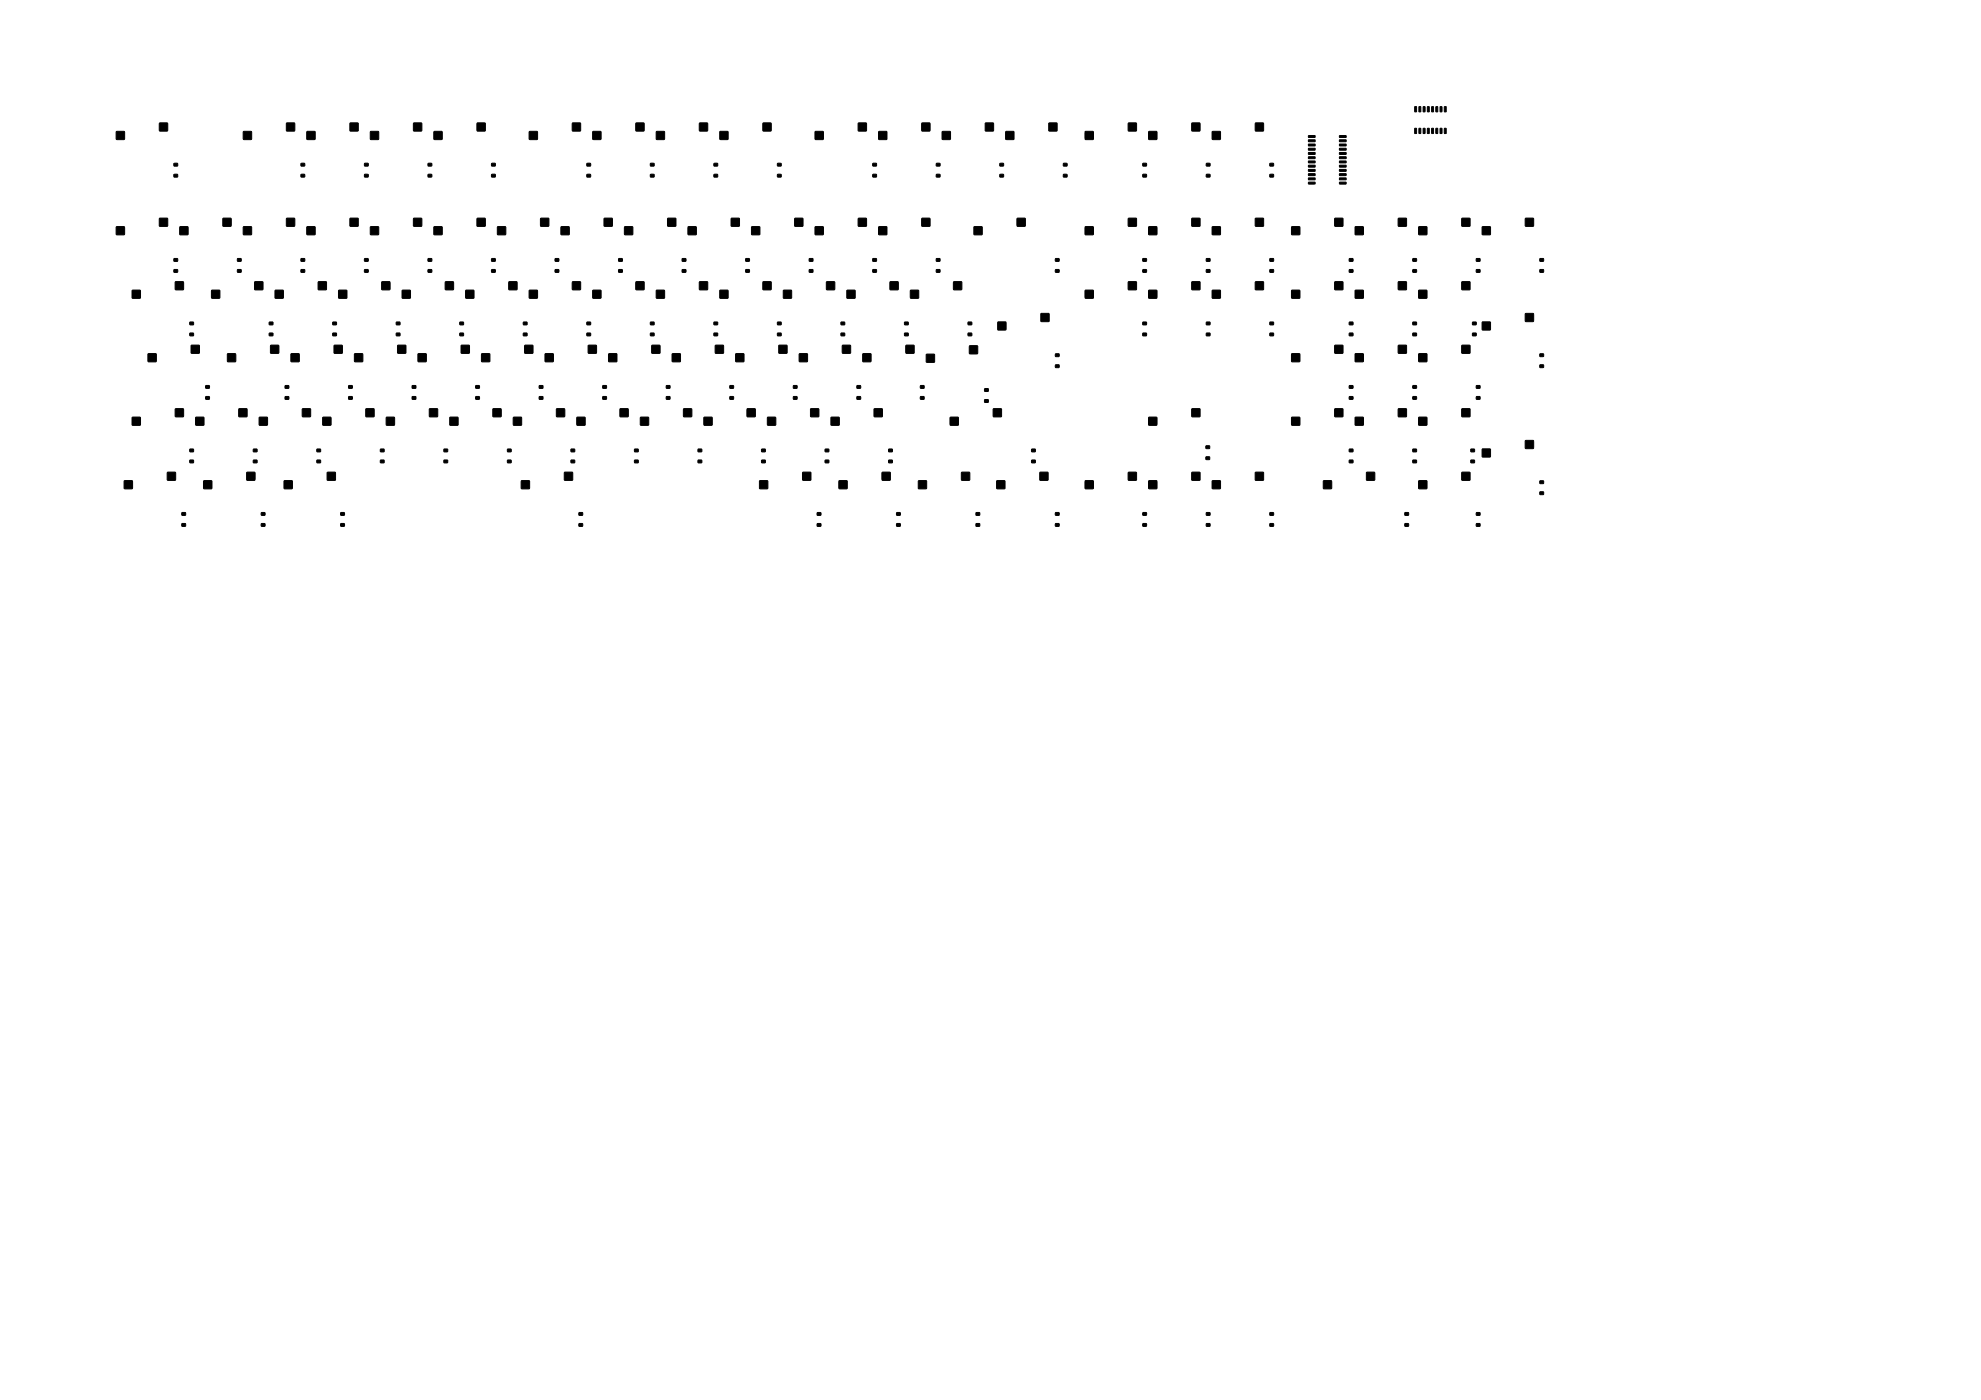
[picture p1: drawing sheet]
<svg xmlns="http://www.w3.org/2000/svg" width="594mm" height="420mm" viewBox="0 0 594 420" stroke-linecap="round" stroke-linejoin="round" font-family="sans-serif">
<g fill="#000" stroke="#000" stroke-width=".3">
<path d="M34.9 39.5h2.4v2.3h-2.4zM47.8 36.9h2.4v2.4h-2.4zM73 39.5h2.4v2.3h-2.4zM85.9 36.9h2.4v2.4h-2.4zM92 39.5h2.4v2.3h-2.4zM105 36.9h2.4v2.4h-2.4zM111.1 39.5h2.4v2.3h-2.4zM124 36.9h2.4v2.4h-2.4zM130.1 39.5h2.4v2.3h-2.4zM143.1 36.9h2.4v2.4h-2.4zM158.7 39.5h2.4v2.3h-2.4zM171.6 36.9h2.4v2.4h-2.4z"/>
<path d="M177.8 39.5h2.4v2.3h-2.4zM190.7 36.9h2.4v2.4h-2.4zM196.8 39.5h2.4v2.3h-2.4zM209.7 36.9h2.4v2.4h-2.4zM215.9 39.5h2.4v2.3h-2.4zM228.8 36.9h2.4v2.4h-2.4zM244.4 39.5h2.4v2.3h-2.4zM257.4 36.9h2.4v2.4h-2.4zM263.5 39.5h2.4v2.3h-2.4zM276.4 36.9h2.4v2.4h-2.4zM282.5 39.5h2.4v2.3h-2.4zM295.5 36.9h2.4v2.4h-2.4z"/>
<path d="M301.6 39.5h2.4v2.3h-2.4zM314.5 36.9h2.4v2.4h-2.4zM325.4 39.5h2.4v2.3h-2.4zM338.3 36.9h2.4v2.4h-2.4zM344.5 39.5h2.4v2.3h-2.4zM357.4 36.9h2.4v2.4h-2.4zM363.5 39.5h2.4v2.3h-2.4zM376.4 36.9h2.4v2.4h-2.4zM424.2 32l.6 .1-.1 1.5-.5-.1zM424.2 38.5l.6 .1-.1 1.5-.5-.1zM425.5 32l.5 .1v1.5l-.5-.1zM425.5 38.5l.5 .1v1.5l-.5-.1z"/>
<path d="M426.8 32l.5 .1-.1 1.5-.5-.1zM426.8 38.5l.5 .1-.1 1.5-.5-.1zM428 32l.6 .1-.1 1.5-.5-.1zM428 38.5l.6 .1-.1 1.5-.5-.1zM429.3 32l.5 .1v1.5l-.5-.1zM429.3 38.5l.5 .1v1.5l-.5-.1zM430.6 32l.5 .1-.1 1.5-.5-.1zM430.6 38.5l.5 .1-.1 1.5-.5-.1zM431.8 32l.6 .1-.1 1.5-.5-.1zM431.8 38.5l.6 .1-.1 1.5-.5-.1zM433.1 32l.6 .1-.1 1.5-.5-.1zM433.1 38.5l.6 .1-.1 1.5-.5-.1z"/>
<path d="M52.2 52.3h1v.8h-1zM52.2 49h1v.8h-1zM90.3 52.3h1v.8h-1zM90.3 49h1v.8h-1zM109.3 52.3h1.1v.8h-1.1zM109.3 49h1.1v.8h-1.1zM128.4 52.3h1v.8h-1zM128.4 49h1v.8h-1zM147.4 52.3h1.1v.8h-1.1zM147.4 49h1.1v.8h-1.1zM176 52.3h1.1v.8h-1.1zM176 49h1.1v.8h-1.1z"/>
<path d="M195 52.3h1.1v.8h-1.1zM195 49h1.1v.8h-1.1zM214.1 52.3h1.1v.8h-1.1zM214.1 49h1.1v.8h-1.1zM233.1 52.3h1.1v.8h-1.1zM233.1 49h1.1v.8h-1.1zM261.7 52.3h1.1v.8h-1.1zM261.7 49h1.1v.8h-1.1zM280.8 52.3h1v.8h-1zM280.8 49h1v.8h-1zM299.8 52.3h1.1v.8h-1.1zM299.8 49h1.1v.8h-1.1z"/>
<path d="M318.9 52.3h1v.8h-1zM318.9 49h1v.8h-1zM342.7 52.3h1.1v.8h-1.1zM342.7 49h1.1v.8h-1.1zM361.7 52.3h1.1v.8h-1.1zM361.7 49h1.1v.8h-1.1zM380.8 52.3h1.1v.8h-1.1zM380.8 49h1.1v.8h-1.1zM392.4 54.7l1.9-.1 .1 .5-2 .1zM392.4 53.4h1.9l.1 .5h-2zM392.4 52.1h1.9l.1 .5-2 .1zM392.4 50.9l1.9-.1 .1 .5-2 .1z"/>
<path d="M392.4 49.6h1.9l.1 .5h-2zM392.4 48.3h1.9l.1 .5-2 .1zM392.4 47.1l1.9-.1 .1 .5-2 .1zM392.4 45.8l1.9-.1 .1 .5-2 .1zM392.4 44.5h1.9l.1 .5-2 .1zM392.4 43.2h1.9l.1 .5-2 .1zM392.4 42l1.9-.1 .1 .5-2 .1zM392.4 40.7h1.9l.1 .5h-2zM401.7 40.7h1.9v.5h-1.9zM401.7 42l1.9-.1v.5l-1.9 .1zM401.7 43.2h1.9v.5l-1.9 .1zM401.7 44.5h1.9v.5l-1.9 .1z"/>
<path d="M401.7 45.8l1.9-.1v.5l-1.9 .1zM401.7 47.1l1.9-.1v.5l-1.9 .1zM401.7 48.3h1.9v.5l-1.9 .1zM401.7 49.6h1.9v.5h-1.9zM401.7 50.9l1.9-.1v.5l-1.9 .1zM401.7 52.1h1.9v.5l-1.9 .1zM401.7 53.4h1.9v.5h-1.9zM401.7 54.7l1.9-.1v.5l-1.9 .1zM34.9 68h2.4v2.4h-2.4zM47.8 65.5h2.4v2.4h-2.4zM52.2 77.6h1v.8h-1zM53.9 68h2.4v2.4h-2.4z"/>
<path d="M66.9 65.5h2.4v2.4h-2.4zM71.2 77.6h1.1v.8h-1.1zM73 68h2.4v2.4h-2.4zM85.9 65.5h2.4v2.4h-2.4zM90.3 77.6h1v.8h-1zM92 68h2.4v2.4h-2.4zM105 65.5h2.4v2.4h-2.4zM109.3 77.6h1.1v.8h-1.1zM111.1 68h2.4v2.4h-2.4zM124 65.5h2.4v2.4h-2.4zM128.4 77.6h1v.8h-1zM130.1 68h2.4v2.4h-2.4z"/>
<path d="M143.1 65.5h2.4v2.4h-2.4zM147.4 77.6h1.1v.8h-1.1zM149.2 68h2.4v2.4h-2.4zM162.1 65.5h2.4v2.4h-2.4zM166.5 77.6h1v.8h-1zM168.2 68h2.4v2.4h-2.4zM181.2 65.5h2.4v2.4h-2.4zM185.5 77.6h1.1v.8h-1.1zM187.3 68h2.4v2.4h-2.4zM200.2 65.5h2.4v2.4h-2.4zM204.6 77.6h1v.8h-1zM206.3 68h2.4v2.4h-2.4z"/>
<path d="M219.3 65.5h2.4v2.4h-2.4zM223.6 77.6h1.1v.8h-1.1zM225.4 68h2.4v2.4h-2.4zM238.3 65.5h2.4v2.4h-2.4zM242.7 77.6h1v.8h-1zM244.4 68h2.4v2.4h-2.4zM257.4 65.5h2.4v2.4h-2.4zM261.7 77.6h1.1v.8h-1.1zM263.5 68h2.4v2.4h-2.4zM276.4 65.5h2.4v2.4h-2.4zM280.8 77.6h1v.8h-1zM292.1 68h2.4v2.4h-2.4z"/>
<path d="M305 65.5h2.4v2.4h-2.4zM316.5 77.6h1.1v.8h-1.1zM325.4 68h2.4v2.4h-2.4zM338.3 65.5h2.4v2.4h-2.4zM342.7 77.6h1.1v.8h-1.1zM344.5 68h2.4v2.4h-2.4zM357.4 65.5h2.4v2.4h-2.4zM361.7 77.6h1.1v.8h-1.1zM363.5 68h2.4v2.4h-2.4zM376.4 65.5h2.4v2.4h-2.4zM380.8 77.6h1.1v.8h-1.1zM387.3 68h2.4v2.4h-2.4z"/>
<path d="M400.2 65.5h2.4v2.4h-2.4zM404.6 77.6h1.1v.8h-1.1zM406.4 68h2.4v2.4h-2.4zM419.3 65.5h2.4v2.4h-2.4zM423.6 77.6h1.1v.8h-1.1zM425.4 68h2.4v2.4h-2.4zM438.3 65.5h2.4v2.4h-2.4zM442.7 77.6h1.1v.8h-1.1zM444.5 68h2.4v2.4h-2.4zM457.4 65.5h2.4v2.4h-2.4zM461.7 77.6h1.1v.8h-1.1zM39.7 87.1h2.4v2.3h-2.4z"/>
<path d="M52.2 80.9h1v.8h-1zM52.6 84.5h2.4v2.4h-2.4zM56.9 96.6h1.1v.8h-1.1zM63.5 87.1h2.4v2.3h-2.4zM71.2 80.9h1.1v.8h-1.1zM76.4 84.5h2.4v2.4h-2.4zM80.7 96.6h1.1v.8h-1.1zM82.5 87.1h2.4v2.3h-2.4zM90.3 80.9h1v.8h-1zM95.4 84.5h2.4v2.4h-2.4zM99.8 96.6h1.1v.8h-1.1zM101.6 87.1h2.4v2.3h-2.4z"/>
<path d="M109.3 80.9h1.1v.8h-1.1zM114.5 84.5h2.4v2.4h-2.4zM118.8 96.6h1.1v.8h-1.1zM120.6 87.1h2.4v2.3h-2.4zM128.4 80.9h1v.8h-1zM133.5 84.5h2.4v2.4h-2.4zM137.9 96.6h1.1v.8h-1.1zM139.7 87.1h2.4v2.3h-2.4zM147.4 80.9h1.1v.8h-1.1zM152.6 84.5h2.4v2.4h-2.4zM156.9 96.6h1.1v.8h-1.1zM158.7 87.1h2.4v2.3h-2.4z"/>
<path d="M166.5 80.9h1v.8h-1zM171.6 84.5h2.4v2.4h-2.4zM176 96.6h1.1v.8h-1.1zM177.8 87.1h2.4v2.3h-2.4zM185.5 80.9h1.1v.8h-1.1zM190.7 84.5h2.4v2.4h-2.4zM195 96.6h1.1v.8h-1.1zM196.8 87.1h2.4v2.3h-2.4zM204.6 80.9h1v.8h-1zM209.7 84.5h2.4v2.4h-2.4zM214.1 96.6h1.1v.8h-1.1zM215.9 87.1h2.4v2.3h-2.4z"/>
<path d="M223.6 80.9h1.1v.8h-1.1zM228.8 84.5h2.4v2.4h-2.4zM233.1 96.6h1.1v.8h-1.1zM234.9 87.1h2.4v2.3h-2.4zM242.7 80.9h1v.8h-1zM247.8 84.5h2.4v2.4h-2.4zM252.2 96.6h1.1v.8h-1.1zM254 87.1h2.4v2.3h-2.4zM261.7 80.9h1.1v.8h-1.1zM266.9 84.5h2.4v2.4h-2.4zM271.2 96.6h1.1v.8h-1.1zM273 87.1h2.4v2.3h-2.4z"/>
<path d="M280.8 80.9h1v.8h-1zM285.9 84.5h2.4v2.4h-2.4zM290.3 96.6h1.1v.8h-1.1zM299.2 96.6h2.4v2.4h-2.4zM312.1 94.1h2.4v2.3h-2.4zM316.5 80.9h1.1v.8h-1.1zM325.4 87.1h2.4v2.3h-2.4zM338.3 84.5h2.4v2.4h-2.4zM342.7 80.9h1.1v.8h-1.1zM342.7 96.6h1.1v.8h-1.1zM344.5 87.1h2.4v2.3h-2.4zM357.4 84.5h2.4v2.4h-2.4z"/>
<path d="M361.7 80.9h1.1v.8h-1.1zM361.7 96.6h1.1v.8h-1.1zM363.5 87.1h2.4v2.3h-2.4zM376.4 84.5h2.4v2.4h-2.4zM380.8 80.9h1.1v.8h-1.1zM380.8 96.6h1.1v.8h-1.1zM387.3 87.1h2.4v2.3h-2.4zM400.2 84.5h2.4v2.4h-2.4zM404.6 96.6h1.1v.8h-1.1zM404.6 80.9h1.1v.8h-1.1zM406.4 87.1h2.4v2.3h-2.4zM419.3 84.5h2.4v2.4h-2.4z"/>
<path d="M423.6 80.9h1.1v.8h-1.1zM423.6 96.6h1.1v.8h-1.1zM425.4 87.1h2.4v2.3h-2.4zM438.3 84.5h2.4v2.4h-2.4zM441.6 96.6h1v.8h-1zM442.7 80.9h1.1v.8h-1.1zM444.5 96.6h2.4v2.4h-2.4zM457.4 94.1h2.4v2.3h-2.4zM461.7 80.9h1.1v.8h-1.1zM44.4 106.1h2.4v2.4h-2.4zM56.9 99.9h1.1v.8h-1.1zM57.3 103.6h2.4v2.4h-2.4z"/>
<path d="M61.7 119h1.1v.8h-1.1zM61.7 115.7h1.1v.8h-1.1zM68.2 106.1h2.4v2.4h-2.4zM80.7 99.9h1.1v.8h-1.1zM81.2 103.6h2.4v2.4h-2.4zM85.5 119h1.1v.8h-1.1zM85.5 115.7h1.1v.8h-1.1zM87.3 106.1h2.4v2.4h-2.4zM99.8 99.9h1.1v.8h-1.1zM100.2 103.6h2.4v2.4h-2.4zM104.6 119h1v.8h-1zM104.6 115.7h1v.8h-1z"/>
<path d="M106.3 106.1h2.4v2.4h-2.4zM118.8 99.9h1.1v.8h-1.1zM119.3 103.6h2.4v2.4h-2.4zM123.6 119h1.1v.8h-1.1zM123.6 115.7h1.1v.8h-1.1zM125.4 106.1h2.4v2.4h-2.4zM137.9 99.9h1.1v.8h-1.1zM138.3 103.6h2.4v2.4h-2.4zM142.7 119h1v.8h-1zM142.7 115.7h1v.8h-1zM144.4 106.1h2.4v2.4h-2.4zM156.9 99.9h1.1v.8h-1.1z"/>
<path d="M157.4 103.6h2.4v2.4h-2.4zM161.7 119h1.1v.8h-1.1zM161.7 115.7h1.1v.8h-1.1zM163.5 106.1h2.4v2.4h-2.4zM176 99.9h1.1v.8h-1.1zM176.4 103.6h2.4v2.4h-2.4zM180.8 119h1v.8h-1zM180.8 115.7h1v.8h-1zM182.5 106.1h2.4v2.4h-2.4zM195 99.9h1.1v.8h-1.1zM195.5 103.6h2.4v2.4h-2.4zM199.8 119h1.1v.8h-1.1z"/>
<path d="M199.8 115.7h1.1v.8h-1.1zM201.6 106.1h2.4v2.4h-2.4zM214.1 99.9h1.1v.8h-1.1zM214.5 103.6h2.4v2.4h-2.4zM218.9 119h1v.8h-1zM218.9 115.7h1v.8h-1zM220.6 106.1h2.4v2.4h-2.4zM233.1 99.9h1.1v.8h-1.1zM233.6 103.6h2.4v2.4h-2.4zM237.9 119h1.1v.8h-1.1zM237.9 115.7h1.1v.8h-1.1zM239.7 106.1h2.4v2.4h-2.4z"/>
<path d="M252.2 99.9h1.1v.8h-1.1zM252.6 103.6h2.4v2.4h-2.4zM257 119h1v.8h-1zM257 115.7h1v.8h-1zM258.7 106.1h2.4v2.4h-2.4zM271.2 99.9h1.1v.8h-1.1zM271.7 103.6h2.4v2.4h-2.4zM276 119h1.1v.8h-1.1zM276 115.7h1.1v.8h-1.1zM277.8 106.3h2.4v2.4h-2.4zM290.3 99.9h1.1v.8h-1.1zM290.7 103.8h2.4v2.3h-2.4z"/>
<path d="M295.2 116.6h1.1v.8h-1.1zM316.5 109.5h1.1v.7h-1.1zM316.5 106.2h1.1v.7h-1.1zM342.7 99.9h1.1v.8h-1.1zM361.7 99.9h1.1v.8h-1.1zM380.8 99.9h1.1v.8h-1.1zM387.3 106.1h2.4v2.4h-2.4zM400.2 103.6h2.4v2.4h-2.4zM404.6 99.9h1.1v.8h-1.1zM404.6 119h1.1v.8h-1.1zM404.6 115.7h1.1v.8h-1.1zM406.4 106.1h2.4v2.4h-2.4z"/>
<path d="M419.3 103.6h2.4v2.4h-2.4zM423.6 119h1.1v.8h-1.1zM423.6 115.7h1.1v.8h-1.1zM423.6 99.9h1.1v.8h-1.1zM425.4 106.1h2.4v2.4h-2.4zM438.3 103.6h2.4v2.4h-2.4zM441.6 99.9h1v.8h-1zM442.7 119h1.1v.8h-1.1zM442.7 115.7h1.1v.8h-1.1zM461.7 109.5h1.1v.7h-1.1zM461.7 106.2h1.1v.7h-1.1zM39.7 125.2h2.4v2.3h-2.4z"/>
<path d="M52.6 122.6h2.4v2.4h-2.4zM56.9 138h1.1v.8h-1.1zM56.9 134.7h1.1v.8h-1.1zM58.7 125.2h2.4v2.3h-2.4zM71.6 122.6h2.4v2.4h-2.4zM76 138h1.1v.8h-1.1zM76 134.7h1.1v.8h-1.1zM77.8 125.2h2.4v2.3h-2.4zM90.7 122.6h2.4v2.4h-2.4zM95 138h1.1v.8h-1.1zM95 134.7h1.1v.8h-1.1zM96.8 125.2h2.4v2.3h-2.4z"/>
<path d="M109.7 122.6h2.4v2.4h-2.4zM114.1 138h1.1v.8h-1.1zM114.1 134.7h1.1v.8h-1.1zM115.9 125.2h2.4v2.3h-2.4zM128.8 122.6h2.4v2.4h-2.4zM133.1 138h1.1v.8h-1.1zM133.1 134.7h1.1v.8h-1.1zM134.9 125.2h2.4v2.3h-2.4zM147.8 122.6h2.4v2.4h-2.4zM152.2 138h1.1v.8h-1.1zM152.2 134.7h1.1v.8h-1.1zM154 125.2h2.4v2.3h-2.4z"/>
<path d="M166.9 122.6h2.4v2.4h-2.4zM171.2 138h1.1v.8h-1.1zM171.2 134.7h1.1v.8h-1.1zM173 125.2h2.4v2.3h-2.4zM185.9 122.6h2.4v2.4h-2.4zM190.3 138h1.1v.8h-1.1zM190.3 134.7h1.1v.8h-1.1zM192.1 125.2h2.4v2.3h-2.4zM205 122.6h2.4v2.4h-2.4zM209.3 138h1.1v.8h-1.1zM209.3 134.7h1.1v.8h-1.1zM211.1 125.2h2.4v2.3h-2.4z"/>
<path d="M224 122.6h2.4v2.4h-2.4zM228.4 138h1.1v.8h-1.1zM228.4 134.7h1.1v.8h-1.1zM230.2 125.2h2.4v2.3h-2.4zM243.1 122.6h2.4v2.4h-2.4zM247.4 138h1.1v.8h-1.1zM247.4 134.7h1.1v.8h-1.1zM249.2 125.2h2.4v2.3h-2.4zM262.1 122.6h2.4v2.4h-2.4zM266.5 138h1.1v.8h-1.1zM266.5 134.7h1.1v.8h-1.1zM284.9 125.2h2.4v2.3h-2.4z"/>
<path d="M295.2 119.9h1.1v.8h-1.1zM297.9 122.6h2.4v2.4h-2.4zM309.3 138h1.1v.8h-1.1zM309.3 134.7h1.1v.8h-1.1zM344.5 125.2h2.4v2.3h-2.4zM357.4 122.6h2.4v2.4h-2.4zM361.6 137.1l1-.1 .1 .8-1 .1zM361.6 133.8h1.1v.7h-1.1zM387.3 125.2h2.4v2.3h-2.4zM400.2 122.6h2.4v2.4h-2.4zM404.6 138h1.1v.8h-1.1zM404.6 134.7h1.1v.8h-1.1z"/>
<path d="M406.4 125.2h2.4v2.3h-2.4zM419.3 122.6h2.4v2.4h-2.4zM423.6 138h1.1v.8h-1.1zM423.6 134.7h1.1v.8h-1.1zM425.4 125.2h2.4v2.3h-2.4zM438.3 122.6h2.4v2.4h-2.4zM441 138h1.1v.8h-1.1zM441 134.7h1.1v.8h-1.1zM444.5 134.7h2.4v2.4h-2.4zM457.4 132.2h2.4v2.3h-2.4zM37.3 144.2h2.4v2.4h-2.4zM50.2 141.7h2.4v2.4h-2.4z"/>
<path d="M54.6 157.1h1v.8h-1zM54.6 153.8h1v.8h-1zM61.1 144.2h2.4v2.4h-2.4zM74 141.7h2.4v2.4h-2.4zM78.4 157.1h1v.8h-1zM78.4 153.8h1v.8h-1zM85.2 144.2h2.4v2.4h-2.4zM98.1 141.7h2.4v2.4h-2.4zM102.2 157.1h1v.8h-1zM102.2 153.8h1v.8h-1zM156.3 144.2h2.4v2.4h-2.4zM169.3 141.7h2.4v2.4h-2.4z"/>
<path d="M173.6 157.1h1.1v.8h-1.1zM173.6 153.8h1.1v.8h-1.1zM227.8 144.2h2.4v2.4h-2.4zM240.7 141.7h2.4v2.4h-2.4zM245.1 157.1h1v.8h-1zM245.1 153.8h1v.8h-1zM251.6 144.2h2.4v2.4h-2.4zM264.5 141.7h2.4v2.4h-2.4zM268.9 157.1h1v.8h-1zM268.9 153.8h1v.8h-1zM275.4 144.2h2.4v2.4h-2.4zM288.3 141.7h2.4v2.4h-2.4z"/>
<path d="M292.7 157.1h1v.8h-1zM292.7 153.8h1v.8h-1zM298.9 144.2h2.4v2.4h-2.4zM311.8 141.7h2.4v2.4h-2.4zM316.5 157.1h1.1v.8h-1.1zM316.5 153.8h1.1v.8h-1.1zM325.4 144.2h2.4v2.4h-2.4zM338.3 141.7h2.4v2.4h-2.4zM342.7 157.1h1.1v.8h-1.1zM342.7 153.8h1.1v.8h-1.1zM344.5 144.2h2.4v2.4h-2.4zM357.4 141.7h2.4v2.4h-2.4z"/>
<path d="M361.7 157.1h1.1v.8h-1.1zM361.7 153.8h1.1v.8h-1.1zM363.5 144.2h2.4v2.4h-2.4zM376.4 141.7h2.4v2.4h-2.4zM380.8 157.1h1.1v.8h-1.1zM380.8 153.8h1.1v.8h-1.1zM396.8 144.2h2.4v2.4h-2.4zM409.8 141.7h2.4v2.4h-2.4zM421.3 157.1h1v.8h-1zM421.3 153.8h1v.8h-1zM425.4 144.2h2.4v2.4h-2.4zM438.3 141.7h2.4v2.4h-2.4z"/>
<path d="M442.7 157.1h1.1v.8h-1.1zM442.7 153.8h1.1v.8h-1.1zM461.7 147.6h1.1v.7h-1.1zM461.7 144.3h1.1v.7h-1.1z"/>
</g>
</svg>
